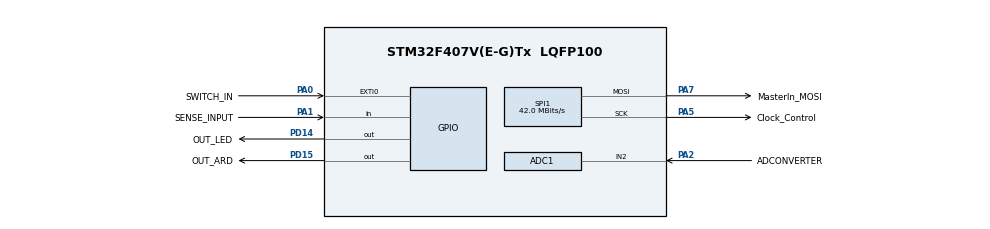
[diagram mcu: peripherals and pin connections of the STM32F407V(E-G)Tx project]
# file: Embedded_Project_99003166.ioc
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ADC1.Channel-0\#ChannelRegularConversion=ADC_CHANNEL_2
ADC1.NbrOfConversionFlag=1
ADC1.Rank-0\#ChannelRegularConversion=1
ADC1.SamplingTime-0\#ChannelRegularConversion=ADC_SAMPLETIME_3CYCLES
ADC1.master=1
Mcu.Family=STM32F4
Mcu.Name=STM32F407V(E-G)Tx
Mcu.Package=LQFP100
NVIC.PriorityGroup=NVIC_PRIORITYGROUP_0
PA0-WKUP.GPIO_Label=SWITCH_IN
PA0-WKUP.Signal=GPXTI0
PA1.GPIO_Label=SENSE_INPUT
PA1.Signal=GPIO_Input
PA13.Mode=Serial_Wire
PA13.Signal=SYS_JTMS-SWDIO
PA14.Mode=Serial_Wire
PA14.Signal=SYS_JTCK-SWCLK
PA2.GPIO_Label=ADCONVERTER
PA2.Signal=ADCx_IN2
PA5.GPIO_Label=Clock_Control
PA5.Mode=TX_Only_Simplex_Unidirect_Master
PA5.Signal=SPI1_SCK
PA7.GPIO_Label=MasterIn_MOSI
PA7.Mode=TX_Only_Simplex_Unidirect_Master
PA7.Signal=SPI1_MOSI
PD14.GPIO_Label=OUT_LED
PD14.Signal=GPIO_Output
PD15.GPIO_Label=OUT_ARD
PD15.Signal=GPIO_Output
ProjectManager.HeapSize=0x200
ProjectManager.StackSize=0x400
ProjectManager.TargetToolchain=STM32CubeIDE
RCC.48MHZClocksFreq_Value=48000000
RCC.AHBFreq_Value=168000000
RCC.APB1CLKDivider=RCC_HCLK_DIV4
RCC.APB1Freq_Value=42000000
RCC.APB1TimFreq_Value=84000000
RCC.APB2CLKDivider=RCC_HCLK_DIV2
RCC.APB2Freq_Value=84000000
RCC.APB2TimFreq_Value=168000000
RCC.CortexFreq_Value=168000000
RCC.HCLKFreq_Value=168000000
RCC.HSE_VALUE=8000000
RCC.HSI_VALUE=16000000
RCC.LSE_VALUE=32768
RCC.PLLM=8
RCC.PLLN=168
RCC.PLLQ=7
RCC.SYSCLKFreq_VALUE=168000000
RCC.SYSCLKSource=RCC_SYSCLKSOURCE_PLLCLK
RCC.VCOOutputFreq_Value=336000000
SH.ADCx_IN2.0=ADC1_IN2,IN2
SPI1.CalculateBaudRate=42.0 MBits/s
SPI1.Direction=SPI_DIRECTION_2LINES
SPI1.Mode=SPI_MODE_MASTER
SPI1.VirtualType=VM_MASTER
board=STM32F407G-DISC1

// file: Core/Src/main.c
/* USER CODE BEGIN Header */
/**
  ******************************************************************************
  * @file           : main.c
  * @brief          : Main program body
  ******************************************************************************
  * @attention
  *
  * <h2><center>&copy; Copyright (c) 2020 STMicroelectronics.
  * All rights reserved.</center></h2>
  *
  * This software component is licensed by ST under Ultimate Liberty license
  * SLA0044, the "License"; You may not use this file except in compliance with
  * the License. You may obtain a copy of the License at:
  *                             www.st.com/SLA0044
  *
  ******************************************************************************
  */
/* USER CODE END Header */
#include "main.h"

/* USER CODE BEGIN Includes */
#include<stdio.h>

/* USER CODE END Includes */

ADC_HandleTypeDef hAdc1;

SPI_HandleTypeDef hSpi1;

/* USER CODE BEGIN PV */
volatile uint8_t Flag_one=0;

/* USER CODE END PV */

void SystemClock_Config(void);
static void MX_GPIO_Init(void);
static void MX_SPI1_Init(void);
static void MX_ADC1_Init(void);

int main(void)
{
  /* USER CODE BEGIN 1 */
	volatile uint32_t ADcVAL=0;
	volatile uint8_t SenSor_InPut=0;
	uint8_t SpI_DaTa;

  /* USER CODE END 1 */

  /* MCU Configuration--------------------------------------------------------*/

  /* Reset of all peripherals, Initializes the Flash interface and the Systick. */
  HAL_Init();

  /* Configure the system clock */
  SystemClock_Config();

  /* Initialize all configured peripherals */
  MX_GPIO_Init();
  MX_SPI1_Init();
  MX_ADC1_Init();

  /* Infinite loop */
  while (1)
  {

    /* USER CODE BEGIN 3 */
	 	  if (Flag_one == 1) //To check flag
	 	  {

	 	  HAL_GPIO_WritePin(OUT_LED_GPIO_Port, OUT_LED_Pin, Flag_one); // To write the output pin
	 	  HAL_Delay(10);

	 	 SenSor_InPut = HAL_GPIO_ReadPin(SENSE_INPUT_GPIO_Port, SENSE_INPUT_Pin); //To copy the value to the temporary variable
	 	  HAL_GPIO_WritePin(SENSE_INPUT_GPIO_Port, SENSE_INPUT_Pin, SenSor_InPut);

	 	  HAL_ADC_Start(&hAdc1);
	 	 	    	 if( HAL_ADC_PollForConversion(&hAdc1, 5) == HAL_OK)
	 	 	    	 {
	 	 	    		ADcVAL=HAL_ADC_GetValue(&hAdc1);
	 	 	    	 }
	 	 	   HAL_Delay(50);
	 	 	 initialise_monitor_handles();

	 	 if(ADcVAL>=512)
	 	 {
	 		 printf("analog value is greater than 512: value is %ld\n",ADcVAL);
	 		SpI_DaTa=SenSor_InPut;
	 		 printf("input sensor status : %d\n",SenSor_InPut);

	 	 }
	 	 else
	 	 {
	 		printf("analog value is less than 512\n");
	 		SpI_DaTa=2;
	 	 }
	 	HAL_SPI_Transmit(&hSpi1, &SpI_DaTa, 1, 10);
	 	  }

	 else
	 	  {
	 		  HAL_GPIO_WritePin(OUT_LED_GPIO_Port, OUT_LED_Pin, Flag_one);
	 		  HAL_Delay(10);

		 	  HAL_GPIO_WritePin(SENSE_INPUT_GPIO_Port, SENSE_INPUT_Pin, 0);
	 	  }
  }

  /* USER CODE END 3 */

}

void SystemClock_Config(void)
{
  RCC_OscInitTypeDef RCC_OscInitStruct = {0};
  RCC_ClkInitTypeDef RCC_ClkInitStruct = {0};

  /** Configure the main internal regulator output voltage
  */
  __HAL_RCC_PWR_CLK_ENABLE();
  __HAL_PWR_VOLTAGESCALING_CONFIG(PWR_REGULATOR_VOLTAGE_SCALE1);
  /** Initializes the RCC Oscillators according to the specified parameters
  * in the RCC_OscInitTypeDef structure.
  */
  RCC_OscInitStruct.OscillatorType = RCC_OSCILLATORTYPE_HSI;
  RCC_OscInitStruct.HSIState = RCC_HSI_ON;
  RCC_OscInitStruct.HSICalibrationValue = RCC_HSICALIBRATION_DEFAULT;
  RCC_OscInitStruct.PLL.PLLState = RCC_PLL_ON;
  RCC_OscInitStruct.PLL.PLLSource = RCC_PLLSOURCE_HSI;
  RCC_OscInitStruct.PLL.PLLM = 8;
  RCC_OscInitStruct.PLL.PLLN = 50;
  RCC_OscInitStruct.PLL.PLLP = RCC_PLLP_DIV2;
  RCC_OscInitStruct.PLL.PLLQ = 7;
  if (HAL_RCC_OscConfig(&RCC_OscInitStruct) != HAL_OK)
  {
    Error_Handler();
  }
  /** Initializes the CPU, AHB and APB buses clocks
  */
  RCC_ClkInitStruct.ClockType = RCC_CLOCKTYPE_HCLK|RCC_CLOCKTYPE_SYSCLK
                              |RCC_CLOCKTYPE_PCLK1|RCC_CLOCKTYPE_PCLK2;
  RCC_ClkInitStruct.SYSCLKSource = RCC_SYSCLKSOURCE_PLLCLK;
  RCC_ClkInitStruct.AHBCLKDivider = RCC_SYSCLK_DIV1;
  RCC_ClkInitStruct.APB1CLKDivider = RCC_HCLK_DIV4;
  RCC_ClkInitStruct.APB2CLKDivider = RCC_HCLK_DIV2;

  if (HAL_RCC_ClockConfig(&RCC_ClkInitStruct, FLASH_LATENCY_1) != HAL_OK)
  {
    Error_Handler();
  }
}

static void MX_ADC1_Init(void)
{

  ADC_ChannelConfTypeDef sConfig = {0};

  /** Configure the global features of the ADC (Clock, Resolution, Data Alignment and number of conversion)
  */
  hAdc1.Instance = ADC1;
  hAdc1.Init.ClockPrescaler = ADC_CLOCK_SYNC_PCLK_DIV2;
  hAdc1.Init.Resolution = ADC_RESOLUTION_10B;
  hAdc1.Init.ScanConvMode = DISABLE;
  hAdc1.Init.ContinuousConvMode = DISABLE;
  hAdc1.Init.DiscontinuousConvMode = DISABLE;
  hAdc1.Init.ExternalTrigConvEdge = ADC_EXTERNALTRIGCONVEDGE_NONE;
  hAdc1.Init.ExternalTrigConv = ADC_SOFTWARE_START;
  hAdc1.Init.DataAlign = ADC_DATAALIGN_RIGHT;
  hAdc1.Init.NbrOfConversion = 1;
  hAdc1.Init.DMAContinuousRequests = DISABLE;
  hAdc1.Init.EOCSelection = ADC_EOC_SINGLE_CONV;
  if (HAL_ADC_Init(&hAdc1) != HAL_OK)
  {
    Error_Handler();
  }
  /** Configure for the selected ADC regular channel its corresponding rank in the sequencer and its sample time.
  */
  sConfig.Channel = ADC_CHANNEL_1;
  sConfig.Rank = 1;
  sConfig.SamplingTime = ADC_SAMPLETIME_28CYCLES;
  if (HAL_ADC_ConfigChannel(&hAdc1, &sConfig) != HAL_OK)
  {
    Error_Handler();
  }

}

static void MX_SPI1_Init(void)
{

  /* SPI1 parameter configuration*/
	hSpi1.Instance = SPI1;
	hSpi1.Init.Mode = SPI_MODE_MASTER;
	hSpi1.Init.Direction = SPI_DIRECTION_2LINES;
	hSpi1.Init.DataSize = SPI_DATASIZE_8BIT;
	hSpi1.Init.CLKPolarity = SPI_POLARITY_LOW;
	hSpi1.Init.CLKPhase = SPI_PHASE_1EDGE;
	hSpi1.Init.NSS = SPI_NSS_SOFT;
	hSpi1.Init.BaudRatePrescaler = SPI_BAUDRATEPRESCALER_256;
	hSpi1.Init.FirstBit = SPI_FIRSTBIT_MSB;
	hSpi1.Init.TIMode = SPI_TIMODE_DISABLE;
	hSpi1.Init.CRCCalculation = SPI_CRCCALCULATION_DISABLE;
	hSpi1.Init.CRCPolynomial = 10;
  if (HAL_SPI_Init(&hSpi1) != HAL_OK)
  {
    Error_Handler();
  }

}

static void MX_GPIO_Init(void)
{
  GPIO_InitTypeDef GPIO_InitStruct = {0};

  /* GPIO Ports Clock Enable */
  __HAL_RCC_GPIOA_CLK_ENABLE();
  __HAL_RCC_GPIOD_CLK_ENABLE();

  /*Configure GPIO pin Output Level */
  HAL_GPIO_WritePin(GPIOD, OUT_LED_Pin|SENSE_INPUT_Pin, GPIO_PIN_RESET);

  /*Configure GPIO pin : PA0 */
  GPIO_InitStruct.Pin = GPIO_PIN_0;
  GPIO_InitStruct.Mode = GPIO_MODE_IT_RISING;
  GPIO_InitStruct.Pull = GPIO_NOPULL;
  HAL_GPIO_Init(GPIOA, &GPIO_InitStruct);

  /*Configure GPIO pin : SensorInput_Pin */
  GPIO_InitStruct.Pin = SENSE_INPUT_Pin;
  GPIO_InitStruct.Mode = GPIO_MODE_INPUT;
  GPIO_InitStruct.Pull = GPIO_PULLDOWN;
  HAL_GPIO_Init(SENSE_INPUT_GPIO_Port, &GPIO_InitStruct);

  /*Configure GPIO pins : PowerLed_Pin SensorLed_Pin */
  GPIO_InitStruct.Pin = OUT_LED_Pin|SENSE_INPUT_Pin;
  GPIO_InitStruct.Mode = GPIO_MODE_OUTPUT_PP;
  GPIO_InitStruct.Pull = GPIO_NOPULL;
  GPIO_InitStruct.Speed = GPIO_SPEED_FREQ_LOW;
  HAL_GPIO_Init(GPIOD, &GPIO_InitStruct);

  /* EXTI interrupt init*/
  HAL_NVIC_SetPriority(EXTI0_IRQn, 0, 0);
  HAL_NVIC_EnableIRQ(EXTI0_IRQn);

}

/* USER CODE BEGIN 4 */
void HAL_GPIO_EXTI_Callback(uint16_t GPIO_Pin)
{
	Flag_one ^=1;
}
/* USER CODE END 4 */

void Error_Handler(void)
{
}

/************************ (C) COPYRIGHT STMicroelectronics *****END OF FILE****/
